# LEF file generated by Abstract Generator version 6.1.5
#
# Contains LEF for all bins.
# Options:   [ ] Antenna
#            [ ] Geometry
#            [x] Technology
# [x] Design rule Document/Antenna rule Document:
# [x] TD-BC15-DR-2001 Revision: 1 2016-03-17


VERSION 5.7 ;
BUSBITCHARS "[]" ;
DIVIDERCHAR "/"  ;

UNITS
    DATABASE MICRONS 1000  ;
END UNITS

MANUFACTURINGGRID 0.001 ;
USEMINSPACING OBS OFF ;

PROPERTYDEFINITIONS
  LAYER LEF58_ENCLOSURE STRING ;
  LAYER LEF58_ENCLOSUREEDGE STRING ;
  LAYER LEF57_ANTENNAGATEPLUSDIFF STRING ;
  LAYER LEF58_ARRAYSPACING STRING ;
END PROPERTYDEFINITIONS

LAYER NW
  TYPE MASTERSLICE ;
END NW

LAYER SN
  TYPE MASTERSLICE ;
END SN

LAYER SP
  TYPE MASTERSLICE ;
END SP

LAYER POLY
    TYPE MASTERSLICE ;
END POLY

LAYER AA
  TYPE MASTERSLICE ;
END AA

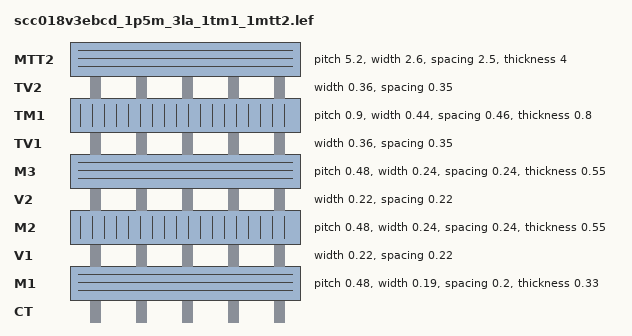
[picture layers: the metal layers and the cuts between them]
LAYER CT
  TYPE CUT ;
END CT

LAYER M1
    TYPE ROUTING ;
    WIDTH 0.190 ;
    MINWIDTH 0.190 ;
    MAXWIDTH 35.00 ;
    SPACING 0.20 ;
    SPACING 0.6 RANGE 10.005 999.0 ;
    SPACING 0.6 RANGE 10.005 999.000 INFLUENCE 1.000  ;
    PITCH 0.480 ;
    OFFSET 0.240 ;
    DIRECTION HORIZONTAL ;
    AREA 0.144 ;
    MINENCLOSEDAREA 0.144 ;
    THICKNESS 0.33 ;
    MINIMUMDENSITY 30 ;
    MAXIMUMDENSITY 70 ;
    ANTENNAMODEL OXIDE1 ;
    ANTENNASIDEAREARATIO 400.0 ;
    ANTENNADIFFSIDEAREARATIO PWL ( ( 0 400 ) ( 0.202 400 ) ( 0.203 2281.2 ) ( 1 2600 ) ) ;
END M1

LAYER V1
    TYPE CUT ;
    WIDTH 0.22 ;
    SPACING 0.22 ;
    ENCLOSURE ABOVE 0.01 0.05 ;
    ENCLOSURE BELOW 0.01 0.05 ;
    ANTENNAMODEL OXIDE1 ;
    ANTENNAAREARATIO 20.0 ;
    ANTENNADIFFAREARATIO  PWL ( ( 0 20 ) ( 0.202 20 ) ( 0.203 91.916 ) ( 1 158.33 ) ) ;
END V1

LAYER M2
    TYPE ROUTING ;
    WIDTH 0.240 ;
    MINWIDTH 0.240 ;
    MAXWIDTH 35.00 ;
    SPACING 0.240 ;
    SPACING 0.6 RANGE 10.005 999.0 ;
    SPACING 0.6 RANGE 10.005 999.000 INFLUENCE 1.000  ;
    PITCH 0.480 ;
    OFFSET 0.240 ;
    DIRECTION VERTICAL ;
    AREA 0.144 ;
    MINENCLOSEDAREA 0.144 ;
    THICKNESS 0.55 ;
    MINIMUMDENSITY 30 ;
    MAXIMUMDENSITY 70 ;
    ANTENNAMODEL OXIDE1 ;
    ANTENNASIDEAREARATIO 400.0 ;
    ANTENNADIFFSIDEAREARATIO PWL ( ( 0 400 ) ( 0.202 400 ) ( 0.203 2281.2 ) ( 1 2600 ) ) ;
END M2

LAYER V2
    TYPE CUT ;
    WIDTH 0.22 ;
    SPACING 0.22 ;
    ENCLOSURE ABOVE 0.01 0.05 ;
    ENCLOSURE BELOW 0.01 0.05 ;
    ANTENNAMODEL OXIDE1 ;
    ANTENNAAREARATIO 20.0 ;
    ANTENNADIFFAREARATIO  PWL ( ( 0 20 ) ( 0.202 20 ) ( 0.203 91.916 ) ( 1 158.33 ) ) ;
END V2

LAYER M3
    TYPE ROUTING ;
    WIDTH 0.240 ;
    MINWIDTH 0.240 ;
    MAXWIDTH 35.00 ;
    SPACING 0.240 ;
    SPACING 0.6 RANGE 10.005 999.0 ;
    SPACING 0.6 RANGE 10.005 999.000 INFLUENCE 1.000  ;
    PITCH 0.480 ;
    OFFSET 0.240 ;
    DIRECTION HORIZONTAL ;
    AREA 0.144 ;
    MINENCLOSEDAREA 0.144 ;
    THICKNESS 0.55 ;
    MINIMUMDENSITY 30 ;
    MAXIMUMDENSITY 70 ;
    ANTENNAMODEL OXIDE1 ;
    ANTENNASIDEAREARATIO 400.0 ;
    ANTENNADIFFSIDEAREARATIO PWL ( ( 0 400 ) ( 0.202 400 ) ( 0.203 2281.2 ) ( 1 2600 ) ) ;
END M3

LAYER TV1
    TYPE CUT ;
    WIDTH 0.36 ;
    SPACING 0.35 ;
    ENCLOSURE BELOW 0.010 0.060 ;
    ENCLOSURE ABOVE 0.09 0.42 ;
    ANTENNAMODEL OXIDE1 ;
    ANTENNAAREARATIO 20.0 ;
    ANTENNADIFFAREARATIO  PWL ( ( 0 20 ) ( 0.202 20 ) ( 0.203 91.916 ) ( 1 158.33 ) ) ;
END TV1

LAYER TM1
    TYPE ROUTING ;
    WIDTH 0.44 ;
    MINWIDTH 0.44 ;
    MAXWIDTH 35.00 ;
    SPACING 0.46 ;
    SPACINGTABLE TWOWIDTHS
    WIDTH     0.00    0.46   1.20
    WIDTH     16.0    1.20   1.20 ;
    PITCH 0.90 ;
    OFFSET 0.45 ;
    DIRECTION VERTICAL ;
    AREA 0.560 ;
    THICKNESS 0.80 ;
    MINIMUMDENSITY 30 ;
    MAXIMUMDENSITY 70 ;
    ANTENNAMODEL OXIDE1 ;
    ANTENNASIDEAREARATIO 400.0 ;
    ANTENNADIFFSIDEAREARATIO PWL ( ( 0 400 ) ( 0.202 400 ) ( 0.203 31624.0 ) ( 1 38000 ) ) ;
END TM1

LAYER TV2
    TYPE CUT ;
    WIDTH 0.36 ;
    SPACING 0.35 ;
    ENCLOSURE BELOW 0.090 0.420 ;
    ENCLOSURE ABOVE 0.4 0.45 ;
    ANTENNAMODEL OXIDE1 ;
    ANTENNAAREARATIO 20.0 ;
    ANTENNADIFFAREARATIO  PWL ( ( 0 20 ) ( 0.202 20 ) ( 0.203 91.916 ) ( 1 158.33 ) ) ;
END TV2

LAYER MTT2
    TYPE ROUTING ;
    WIDTH 2.60 ;
    MINWIDTH 2.60 ;
    MAXWIDTH 35.00 ;
    SPACING 2.50 ;
    SPACINGTABLE TWOWIDTHS
    WIDTH     0.00    2.50   4.00
    WIDTH     16.0    4.00   4.00 ;
    PITCH 5.20 ;
    OFFSET 2.60 ;
    DIRECTION HORIZONTAL ;
    AREA 6.760 ;
    THICKNESS 4.00 ;
    MINIMUMDENSITY 30 ;
    MAXIMUMDENSITY 75 ;
    ANTENNAMODEL OXIDE1 ;
    ANTENNASIDEAREARATIO 400.0 ;
    ANTENNADIFFSIDEAREARATIO PWL ( ( 0 400 ) ( 0.202 400 ) ( 0.203 31624.0 ) ( 1 38000 ) ) ;
END MTT2

LAYER OVERLAP
    TYPE OVERLAP ;
END OVERLAP

VIA V1_H DEFAULT  # AUTOGEN
 RESISTANCE 5.0000e+00 ;
  LAYER M1 ;
    RECT  -0.160 -0.120 0.160 0.120 ;
  LAYER M2 ;
    RECT  -0.160 -0.120 0.160 0.120 ;
  LAYER V1 ;
    RECT -0.110 -0.110 0.110 0.110 ;
END V1_H

VIA V1_V DEFAULT  # AUTOGEN
 RESISTANCE 5.0000e+00 ;
  LAYER M1 ;
    RECT  -0.120 -0.160 0.120 0.160 ;
  LAYER M2 ;
    RECT  -0.120 -0.160 0.120 0.160 ;
  LAYER V1 ;
    RECT -0.110 -0.110 0.110 0.110 ;
END V1_V

VIA V1_X DEFAULT  # AUTOGEN
 RESISTANCE 5.0000e+00 ;
  LAYER M1 ;
    RECT  -0.160 -0.120 0.160 0.120 ;
  LAYER M2 ;
    RECT  -0.120 -0.160 0.120 0.160 ;
  LAYER V1 ;
    RECT -0.110 -0.110 0.110 0.110 ;
END V1_X

VIA V1_XR DEFAULT  # AUTOGEN
 RESISTANCE 5.0000e+00 ;
  LAYER M1 ;
    RECT  -0.120 -0.160 0.120 0.160 ;
  LAYER M2 ;
    RECT  -0.160 -0.120 0.160 0.120 ;
  LAYER V1 ;
    RECT -0.110 -0.110 0.110 0.110 ;
END V1_XR

VIA V2_H DEFAULT  # AUTOGEN
 RESISTANCE 5.0000e+00 ;
  LAYER M2 ;
    RECT  -0.160 -0.120 0.160 0.120 ;
  LAYER M3 ;
    RECT  -0.160 -0.120 0.160 0.120 ;
  LAYER V2 ;
    RECT -0.110 -0.110 0.110 0.110 ;
END V2_H

VIA V2_V DEFAULT  # AUTOGEN
 RESISTANCE 5.0000e+00 ;
  LAYER M2 ;
    RECT  -0.120 -0.160 0.120 0.160 ;
  LAYER M3 ;
    RECT  -0.120 -0.160 0.120 0.160 ;
  LAYER V2 ;
    RECT -0.110 -0.110 0.110 0.110 ;
END V2_V

VIA V2_X DEFAULT  # AUTOGEN
 RESISTANCE 5.0000e+00 ;
  LAYER M2 ;
    RECT  -0.160 -0.120 0.160 0.120 ;
  LAYER M3 ;
    RECT  -0.120 -0.160 0.120 0.160 ;
  LAYER V2 ;
    RECT -0.110 -0.110 0.110 0.110 ;
END V2_X

VIA V2_XR DEFAULT  # AUTOGEN
 RESISTANCE 5.0000e+00 ;
  LAYER M2 ;
    RECT  -0.120 -0.160 0.120 0.160 ;
  LAYER M3 ;
    RECT  -0.160 -0.120 0.160 0.120 ;
  LAYER V2 ;
    RECT -0.110 -0.110 0.110 0.110 ;
END V2_XR

VIA V1_2CUT_E DEFAULT  # AUTOGEN
 RESISTANCE 2.5000e+00 ;
  LAYER M1 ;
    RECT  -0.160 -0.120 0.600 0.120 ;
  LAYER M2 ;
    RECT  -0.160 -0.120 0.600 0.120 ;
  LAYER V1 ;
    RECT -0.110 -0.110 0.110 0.110 ;
    RECT 0.330 -0.110 0.550 0.110 ;
END V1_2CUT_E

VIA V1_2CUT_W DEFAULT  # AUTOGEN
 RESISTANCE 2.5000e+00 ;
  LAYER M1 ;
    RECT  -0.600 -0.120 0.160 0.120 ;
  LAYER M2 ;
    RECT  -0.600 -0.120 0.160 0.120 ;
  LAYER V1 ;
    RECT -0.550 -0.110 -0.330 0.110 ;
    RECT -0.110 -0.110 0.110 0.110 ;
END V1_2CUT_W

VIA V1_2CUT_N DEFAULT  # AUTOGEN
 RESISTANCE 2.5000e+00 ;
  LAYER M1 ;
    RECT  -0.120 -0.160 0.120 0.600 ;
  LAYER M2 ;
    RECT  -0.120 -0.160 0.120 0.600 ;
  LAYER V1 ;
    RECT -0.110 -0.110 0.110 0.110 ;
    RECT -0.110 0.330 0.110 0.550 ;
END V1_2CUT_N

VIA V1_2CUT_S DEFAULT  # AUTOGEN
 RESISTANCE 2.5000e+00 ;
  LAYER M1 ;
    RECT  -0.120 -0.600 0.120 0.160 ;
  LAYER M2 ;
    RECT  -0.120 -0.600 0.120 0.160 ;
  LAYER V1 ;
    RECT -0.110 -0.550 0.110 -0.330 ;
    RECT -0.110 -0.110 0.110 0.110 ;
END V1_2CUT_S

VIA V2_2CUT_E DEFAULT  # AUTOGEN
 RESISTANCE 2.5000e+00 ;
  LAYER M2 ;
    RECT  -0.160 -0.120 0.600 0.120 ;
  LAYER M3 ;
    RECT  -0.160 -0.120 0.600 0.120 ;
  LAYER V2 ;
    RECT -0.110 -0.110 0.110 0.110 ;
    RECT 0.330 -0.110 0.550 0.110 ;
END V2_2CUT_E

VIA V2_2CUT_W DEFAULT  # AUTOGEN
 RESISTANCE 2.5000e+00 ;
  LAYER M2 ;
    RECT  -0.600 -0.120 0.160 0.120 ;
  LAYER M3 ;
    RECT  -0.600 -0.120 0.160 0.120 ;
  LAYER V2 ;
    RECT -0.550 -0.110 -0.330 0.110 ;
    RECT -0.110 -0.110 0.110 0.110 ;
END V2_2CUT_W

VIA V2_2CUT_N DEFAULT  # AUTOGEN
 RESISTANCE 2.5000e+00 ;
  LAYER M2 ;
    RECT  -0.120 -0.160 0.120 0.600 ;
  LAYER M3 ;
    RECT  -0.120 -0.160 0.120 0.600 ;
  LAYER V2 ;
    RECT -0.110 -0.110 0.110 0.110 ;
    RECT -0.110 0.330 0.110 0.550 ;
END V2_2CUT_N

VIA V2_2CUT_S DEFAULT  # AUTOGEN
 RESISTANCE 2.5000e+00 ;
  LAYER M2 ;
    RECT  -0.120 -0.600 0.120 0.160 ;
  LAYER M3 ;
    RECT  -0.120 -0.600 0.120 0.160 ;
  LAYER V2 ;
    RECT -0.110 -0.550 0.110 -0.330 ;
    RECT -0.110 -0.110 0.110 0.110 ;
END V2_2CUT_S

VIARULE VIA1ARRAY GENERATE
  LAYER M1 ;
      ENCLOSURE 0.05 0.01 ;
  LAYER M2 ;
      ENCLOSURE 0.05 0.01 ;
  LAYER V1 ;
    RECT -0.110 -0.110 0.110 0.110 ;
    SPACING 0.500 BY 0.500 ;
END VIA1ARRAY

VIARULE VIA2ARRAY GENERATE
  LAYER M2 ;
      ENCLOSURE 0.05 0.01 ;
  LAYER M3 ;
      ENCLOSURE 0.05 0.01 ;
  LAYER V2 ;
    RECT -0.110 -0.110 0.110 0.110 ;
    SPACING 0.500 BY 0.500 ;
END VIA2ARRAY

VIA TV1_H DEFAULT  # AUTOGEN
 RESISTANCE 5.0000e+00 ;
  LAYER M3 ;
    RECT  -0.240 -0.190 0.240 0.190 ;
  LAYER TM1 ;
    RECT  -0.600 -0.270 0.600 0.270 ;
  LAYER TV1 ;
    RECT -0.180 -0.180 0.180 0.180 ;
END TV1_H

VIA TV1_V DEFAULT  # AUTOGEN
 RESISTANCE 5.0000e+00 ;
  LAYER M3 ;
    RECT  -0.190 -0.240 0.190 0.240 ;
  LAYER TM1 ;
    RECT  -0.270 -0.600 0.270 0.600 ;
  LAYER TV1 ;
    RECT -0.180 -0.180 0.180 0.180 ;
END TV1_V

VIA TV1_X DEFAULT  # AUTOGEN
 RESISTANCE 5.0000e+00 ;
  LAYER M3 ;
    RECT  -0.240 -0.190 0.240 0.190 ;
  LAYER TM1 ;
    RECT  -0.270 -0.600 0.270 0.600 ;
  LAYER TV1 ;
    RECT -0.180 -0.180 0.180 0.180 ;
END TV1_X

VIA TV1_XR DEFAULT  # AUTOGEN
 RESISTANCE 5.0000e+00 ;
  LAYER M3 ;
    RECT  -0.190 -0.240 0.190 0.240 ;
  LAYER TM1 ;
    RECT  -0.600 -0.270 0.600 0.270 ;
  LAYER TV1 ;
    RECT -0.180 -0.180 0.180 0.180 ;
END TV1_XR

VIA TV1_2CUT_E DEFAULT  # AUTOGEN
 RESISTANCE 2.5000e+00 ;
  LAYER M3 ;
    RECT  -0.240 -0.190 0.820 0.190 ;
  LAYER TM1 ;
    RECT  -0.600 -0.270 1.180 0.270 ;
  LAYER TV1 ;
    RECT -0.180 -0.180 0.180 0.180 ;
    RECT 0.400 -0.180 0.760 0.180 ;
END TV1_2CUT_E

VIA TV1_2CUT_W DEFAULT  # AUTOGEN
 RESISTANCE 2.5000e+00 ;
  LAYER M3 ;
    RECT  -0.820 -0.190 0.240 0.190 ;
  LAYER TM1 ;
    RECT  -1.180 -0.270 0.600 0.270 ;
  LAYER TV1 ;
    RECT -0.760 -0.180 -0.400 0.180 ;
    RECT -0.180 -0.180 0.180 0.180 ;
END TV1_2CUT_W

VIA TV1_2CUT_N DEFAULT  # AUTOGEN
 RESISTANCE 2.5000e+00 ;
  LAYER M3 ;
    RECT  -0.190 -0.240 0.190 0.820 ;
  LAYER TM1 ;
    RECT  -0.270 -0.600 0.270 1.180 ;
  LAYER TV1 ;
    RECT -0.180 -0.180 0.180 0.180 ;
    RECT -0.180 0.400 0.180 0.760 ;
END TV1_2CUT_N

VIA TV1_2CUT_S DEFAULT  # AUTOGEN
 RESISTANCE 2.5000e+00 ;
  LAYER M3 ;
    RECT  -0.190 -0.820 0.190 0.240 ;
  LAYER TM1 ;
    RECT  -0.270 -1.180 0.270 0.600 ;
  LAYER TV1 ;
    RECT -0.180 -0.760 0.180 -0.400 ;
    RECT -0.180 -0.180 0.180 0.180 ;
END TV1_2CUT_S

VIARULE TVIA1ARRAY GENERATE
  LAYER M3 ;
      ENCLOSURE 0.06 0.01 ;
  LAYER TM1 ;
      ENCLOSURE 0.42 0.09 ;
  LAYER TV1 ;
    RECT -0.180 -0.180 0.180 0.180 ;
    SPACING 0.710 BY 0.710 ;
END TVIA1ARRAY

VIA TV2_H DEFAULT  # AUTOGEN
 RESISTANCE 2.0000e+00 ;
  LAYER TM1 ;
    RECT  -0.600 -0.270 0.600 0.270 ;
  LAYER MTT2 ;
    RECT  -0.630 -0.580 0.630 0.580 ;
  LAYER TV2 ;
    RECT -0.180 -0.180 0.180 0.180 ;
END TV2_H

VIA TV2_V DEFAULT  # AUTOGEN
 RESISTANCE 2.0000e+00 ;
  LAYER TM1 ;
    RECT  -0.270 -0.600 0.270 0.600 ;
  LAYER MTT2 ;
    RECT  -0.580 -0.630 0.580 0.630 ;
  LAYER TV2 ;
    RECT -0.180 -0.180 0.180 0.180 ;
END TV2_V

VIA TV2_X DEFAULT  # AUTOGEN
 RESISTANCE 2.0000e+00 ;
  LAYER TM1 ;
    RECT  -0.600 -0.270 0.600 0.270 ;
  LAYER MTT2 ;
    RECT  -0.580 -0.630 0.580 0.630 ;
  LAYER TV2 ;
    RECT -0.180 -0.180 0.180 0.180 ;
END TV2_X

VIA TV2_XR DEFAULT  # AUTOGEN
 RESISTANCE 2.0000e+00 ;
  LAYER TM1 ;
    RECT  -0.270 -0.600 0.270 0.600 ;
  LAYER MTT2 ;
    RECT  -0.630 -0.580 0.630 0.580 ;
  LAYER TV2 ;
    RECT -0.180 -0.180 0.180 0.180 ;
END TV2_XR

VIA TV2_2CUT_E DEFAULT  # AUTOGEN
 RESISTANCE 2.5000e+00 ;
  LAYER TM1 ;
    RECT  -0.600 -0.270 1.180 0.270 ;
  LAYER MTT2 ;
    RECT  -0.630 -0.580 1.210 0.580 ;
  LAYER TV2 ;
    RECT -0.180 -0.180 0.180 0.180 ;
    RECT 0.400 -0.180 0.760 0.180 ;
END TV2_2CUT_E

VIA TV2_2CUT_W DEFAULT  # AUTOGEN
 RESISTANCE 2.5000e+00 ;
  LAYER TM1 ;
    RECT  -1.180 -0.270 0.600 0.270 ;
  LAYER MTT2 ;
    RECT  -1.210 -0.580 0.630 0.580 ;
  LAYER TV2 ;
    RECT -0.760 -0.180 -0.400 0.180 ;
    RECT -0.180 -0.180 0.180 0.180 ;
END TV2_2CUT_W

VIA TV2_2CUT_N DEFAULT  # AUTOGEN
 RESISTANCE 2.5000e+00 ;
  LAYER TM1 ;
    RECT  -0.270 -0.600 0.270 1.180 ;
  LAYER MTT2 ;
    RECT  -0.580 -0.630 0.580 1.210 ;
  LAYER TV2 ;
    RECT -0.180 -0.180 0.180 0.180 ;
    RECT -0.180 0.400 0.180 0.760 ;
END TV2_2CUT_N

VIA TV2_2CUT_S DEFAULT  # AUTOGEN
 RESISTANCE 2.5000e+00 ;
  LAYER TM1 ;
    RECT  -0.270 -1.180 0.270 0.600 ;
  LAYER MTT2 ;
    RECT  -0.580 -1.210 0.580 0.630 ;
  LAYER TV2 ;
    RECT -0.180 -0.760 0.180 -0.400 ;
    RECT -0.180 -0.180 0.180 0.180 ;
END TV2_2CUT_S

VIARULE TVIA2ARRAY GENERATE
  LAYER TM1 ;
      ENCLOSURE 0.42 0.09 ;
  LAYER MTT2 ;
      ENCLOSURE 0.45 0.4 ;
  LAYER TV2 ;
    RECT -0.180 -0.180 0.180 0.180 ;
    SPACING 0.710 BY 0.710 ;
END TVIA2ARRAY
END LIBRARY
